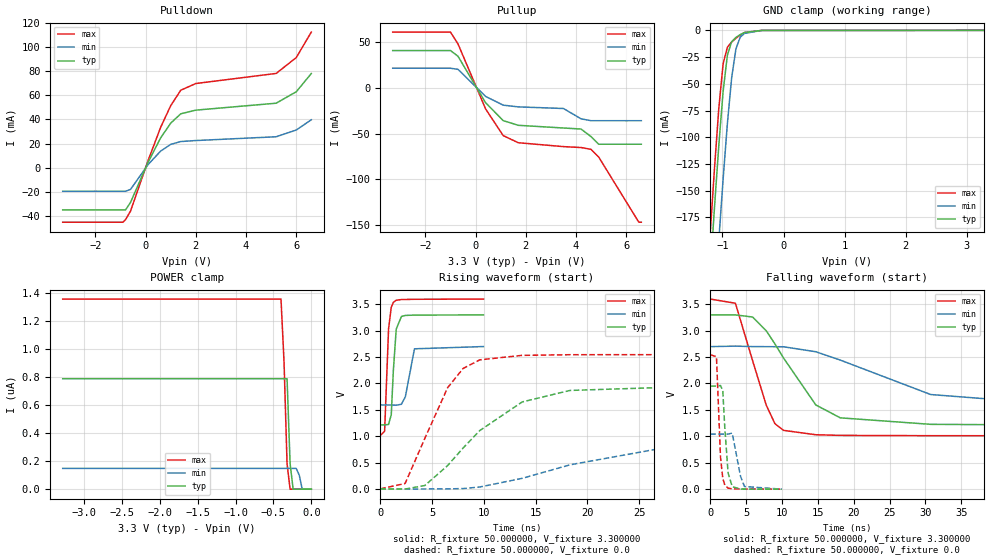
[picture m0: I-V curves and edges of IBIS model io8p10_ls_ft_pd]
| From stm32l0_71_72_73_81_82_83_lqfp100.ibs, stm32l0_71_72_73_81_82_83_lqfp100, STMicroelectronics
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|   Model io8p10_ls_ft_pd
[Model]  io8p10_ls_ft_pd
Model_type I/O
Polarity   Non-Inverting
Enable   Active-Low
Vinl =   0.990000V
Vinh =   2.310000V
Vmeas =  1.650000V
Cref =   50.000000pF
Rref =   100.000000M
Vref =   0.0V
C_comp   4.606100pF   4.563500pF   4.706200pF
[Temperature Range]   25.000000   0.125000k   -40.000000
[Pullup Reference]   3.300000V   2.700000V   3.600000V
[Pulldown Reference]   0.0V   0.0V   0.0V
[POWER Clamp Reference]   3.300000V   2.700000V   3.600000V
[GND Clamp Reference]   0.0V   0.0V   0.0V
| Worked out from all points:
|   slope of the pulldown table from 0 to 0.495 V, typ, clamps not added: 23.6 ohm
|   slope of the pullup table from 0 to 0.495 V, typ, clamps not added: 24.9 ohm
|   GND clamp passes 1 mA (typ) near -0.59 V on its own axis
|   rising waveform, R_fixture 50.000000, V_fixture 3.300000: 20-80 % time 317ps typ, 426ps min, 300ps max; typ from 1.21 V to 3.3 V
|   rising waveform, R_fixture 50.000000, V_fixture 0.0: 20-80 % time 6.51ns typ, 13.6ns min, 3.48ns max; typ from 0 V to 1.95 V
|   falling waveform, R_fixture 50.000000, V_fixture 3.300000: 20-80 % time 6.08ns typ, 12.6ns min, 3.34ns max; typ from 3.3 V to 1.21 V
|   falling waveform, R_fixture 50.000000, V_fixture 0.0: 20-80 % time 520ps typ, 682ps min, 458ps max; typ from 1.95 V to 0 V
[Pulldown]
|Voltage   I(typ)   I(min)   I(max)
-3.3V     -34.78mA   -19.34mA   -44.89mA
-900mV    -34.78mA   -19.34mA   -44.89mA
-800mV    -34.78mA   -19.34mA   -42.84mA
-600mV    -28.56mA   -17.8mA    -35.74mA
100mV     4.638mA    2.744mA    6.076mA
600mV     24.8mA     13.84mA    33.52mA
1V        36.92mA    19.39mA    51.35mA
1.4V      44.67mA    21.76mA    64.17mA
2V        47.7mA     22.58mA    69.7mA
5.2V      53.44mA    25.71mA    78.04mA
6V        62.89mA    31.28mA    91.14mA
6.6V      77.95mA    39.75mA    112.2mA
[Pullup]
|Voltage   I(typ)   I(min)   I(max)
-3.3V     40.48mA    21.18mA    60.57mA
-1V       40.48mA    21.18mA    60.57mA
-700mV    34.22mA    19.98mA    47.65mA
400mV     -16.48mA   -9.566mA   -23.24mA
1.1V      -35.89mA   -19.06mA   -52.22mA
1.7V      -41.02mA   -20.95mA   -60.01mA
3.5V      -43.95mA   -22.7mA    -64.24mA
4.2V      -45.08mA   -33.97mA   -65.24mA
4.6V      -53.38mA   -36mA      -67.23mA
4.9V      -61.64mA   -36mA      -75.5mA
6.5V      -61.64mA   -36mA      -146.6mA
6.6V      -61.64mA   -36mA      -146.6mA
[GND_clamp]
|Voltage   I(typ)   I(min)   I(max)
-3.3V     -2.275A    -2.356A    -2.249A
-1.2V     -226mA     -318.7mA   -189.2mA
-1.13V    -164.9mA   -256.6mA   -128.3mA
-1.06V    -107.5mA   -196.5mA   -72.79mA
-990mV    -57.33mA   -139.4mA   -31.4mA
-920mV    -23.23mA   -87.33mA   -15.73mA
-850mV    -10.59mA   -44.46mA   -10.94mA
-780mV    -6.551mA   -17.26mA   -7.364mA
-710mV    -3.945mA   -6.365mA   -4.316mA
-640mV    -1.966mA   -2.806mA   -1.983mA
-360mV    -10.16uA   -28.12uA   -6.105uA
3.28V     73.92uA    88.6uA     51.45uA
[POWER_clamp]
|Voltage   I(typ)   I(min)   I(max)
-3.28V    786.7nA    148nA      1.355uA
-400mV    786.7nA    148nA      1.355uA
-360mV    786.7nA    148nA      908.2nA
-320mV    786.7nA    148nA      180.5nA
-280mV    182.6nA    148nA      0A
-240mV    0A         148nA      0A
-200mV    0A         148nA      0A
-160mV    0A         101.6nA    0A
-120mV    0A         0A         0A
0V        0A         0A         0A
[Ramp]
| variable   typ   min   max
dV/dt_r  1.17009/6.49858n   0.61787/13.51358n   1.52712/3.47686n
dV/dt_f  1.25100/6.07192n   0.64098/12.43359n   1.55262/3.33325n
R_load = 50.000000
[Rising Waveform]
R_fixture= 50.000000
V_fixture= 3.300000
V_fixture_min= 2.700000
V_fixture_max= 3.600000
|time   V(typ)   V(min)   V(max)
0s        1.213V     1.591V     1.011V
420.4ps   1.212V     1.591V     1.095V
800.8ps   1.222V     1.591V     3.033V
1.061ns   1.405V     1.591V     3.443V
1.261ns   2.236V     1.589V     3.535V
1.542ns   3.029V     1.586V     3.575V
2.042ns   3.267V     1.604V     3.589V
2.422ns   3.288V     1.746V     3.59V
3.303ns   3.294V     2.655V     3.594V
9.97ns    3.298V     2.698V     3.598V
[Rising Waveform]
R_fixture= 50.000000
V_fixture= 0.0
V_fixture_min= 0.0
V_fixture_max= 0.0
|time   V(typ)   V(min)   V(max)
0s        172.6uV    66.71uV    965uV
2.402ns   -2.737mV   -5.252mV   102.4mV
4.304ns   63.98mV    -1.082mV   956.7mV
6.507ns   441.7mV    -335.5uV   1.918V
8.008ns   776.3mV    6.19mV     2.283V
9.61ns    1.105V     35.45mV    2.446V
13.71ns   1.648V     200.1mV    2.531V
18.32ns   1.866V     455.7mV    2.543V
31.43ns   1.948V     920.7mV    2.545V
49.85ns   1.95V      1.042V     2.545V
[Falling Waveform]
R_fixture= 50.000000
V_fixture= 3.300000
V_fixture_min= 2.700000
V_fixture_max= 3.600000
|time   V(typ)   V(min)   V(max)
0s        3.298V     2.698V     3.598V
3.504ns   3.298V     2.707V     3.519V
5.906ns   3.258V     2.699V     2.429V
7.808ns   2.996V     2.697V     1.588V
9.009ns   2.75V      2.696V     1.24V
10.21ns   2.483V     2.695V     1.113V
14.71ns   1.594V     2.601V     1.03V
18.12ns   1.35V      2.443V     1.018V
30.73ns   1.227V     1.791V     1.012V
49.85ns   1.213V     1.591V     1.011V
[Falling Waveform]
R_fixture= 50.000000
V_fixture= 0.0
V_fixture_min= 0.0
V_fixture_max= 0.0
|time   V(typ)   V(min)   V(max)
0s        1.95V      1.042V     2.545V
860.9ps   1.95V      1.042V     2.506V
1.421ns   1.962V     1.042V     613.8mV
1.742ns   1.867V     1.042V     204.1mV
2.022ns   1.172V     1.042V     79.75mV
2.482ns   307.5mV    1.042V     19.76mV
3.063ns   47.54mV    1.062V     6.106mV
4.204ns   2.45mV     248.9mV    3.951mV
4.765ns   1.646mV    50.63mV    2.881mV
9.97ns    172.6uV    66.71uV    965uV
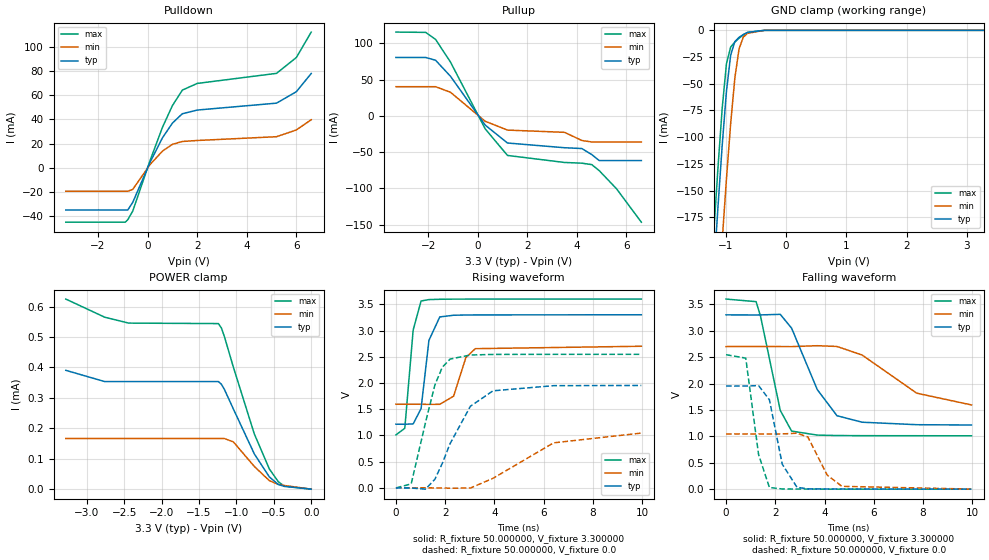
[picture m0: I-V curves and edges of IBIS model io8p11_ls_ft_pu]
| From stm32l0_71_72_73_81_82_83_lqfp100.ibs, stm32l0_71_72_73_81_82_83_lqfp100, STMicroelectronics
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|   Model io8p11_ls_ft_pu
[Model]  io8p11_ls_ft_pu
Model_type I/O
Polarity   Non-Inverting
Enable   Active-Low
Vinl =   0.990000V
Vinh =   2.310000V
Vmeas =  1.650000V
Cref =   50.000000pF
Rref =   100.000000M
Vref =   0.0V
C_comp   4.606100pF   4.563500pF   4.706200pF
[Temperature Range]   25.000000   0.125000k   -40.000000
[Pullup Reference]   3.300000V   2.700000V   3.600000V
[Pulldown Reference]   0.0V   0.0V   0.0V
[POWER Clamp Reference]   3.300000V   2.700000V   3.600000V
[GND Clamp Reference]   0.0V   0.0V   0.0V
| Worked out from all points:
|   slope of the pulldown table from 0 to 0.495 V, typ, clamps not added: 23.6 ohm
|   slope of the pullup table from 0 to 0.495 V, typ, clamps not added: 24.9 ohm
|   GND clamp passes 1 mA (typ) near -0.59 V on its own axis
|   rising waveform, R_fixture 50.000000, V_fixture 3.300000: 20-80 % time 319ps typ, 429ps min, 281ps max; typ from 1.22 V to 3.3 V
|   rising waveform, R_fixture 50.000000, V_fixture 0.0: 20-80 % time 1.22ns typ, 2.23ns min, 756ps max; typ from 0.002 V to 1.95 V
|   falling waveform, R_fixture 50.000000, V_fixture 3.300000: 20-80 % time 1.19ns typ, 2.02ns min, 694ps max; typ from 3.3 V to 1.22 V
|   falling waveform, R_fixture 50.000000, V_fixture 0.0: 20-80 % time 531ps typ, 696ps min, 441ps max; typ from 1.95 V to 0.002 V
[Pulldown]
|Voltage   I(typ)   I(min)   I(max)
-3.3V     -34.78mA   -19.34mA   -44.89mA
-900mV    -34.78mA   -19.34mA   -44.89mA
-800mV    -34.78mA   -19.34mA   -42.84mA
-600mV    -28.56mA   -17.8mA    -35.75mA
100mV     4.638mA    2.744mA    6.076mA
600mV     24.8mA     13.84mA    33.52mA
1V        36.93mA    19.4mA     51.35mA
1.4V      44.67mA    21.76mA    64.17mA
2V        47.71mA    22.58mA    69.7mA
5.2V      53.42mA    25.71mA    78.01mA
6V        62.87mA    31.27mA    91.1mA
6.6V      77.92mA    39.75mA    112.1mA
[Pullup]
|Voltage   I(typ)   I(min)   I(max)
-3.3V     80.52mA    40.21mA    115.5mA
-2.1V     80.52mA    40.21mA    115.1mA
-1.7V     76.64mA    40.21mA    105.4mA
-1.1V     54.61mA    32.55mA    74.2mA
300mV     -12.7mA    -7.449mA   -17.83mA
1.2V      -37.42mA   -19.62mA   -54.57mA
3.5V      -43.94mA   -22.7mA    -64.24mA
4.2V      -45.07mA   -33.96mA   -65.24mA
4.6V      -53.38mA   -35.99mA   -67.22mA
4.9V      -61.63mA   -35.99mA   -75.49mA
5.6V      -61.63mA   -35.99mA   -100.6mA
6.6V      -61.63mA   -35.99mA   -146.6mA
[GND_clamp]
|Voltage   I(typ)   I(min)   I(max)
-3.3V     -2.275A    -2.356A    -2.249A
-1.2V     -226mA     -318.7mA   -189.2mA
-1.13V    -164.9mA   -256.6mA   -128.3mA
-1.06V    -107.5mA   -196.5mA   -72.78mA
-990mV    -57.32mA   -139.4mA   -31.39mA
-920mV    -23.22mA   -87.32mA   -15.73mA
-850mV    -10.58mA   -44.45mA   -10.94mA
-780mV    -6.539mA   -17.25mA   -7.356mA
-710mV    -3.933mA   -6.349mA   -4.308mA
-640mV    -1.955mA   -2.79mA    -1.975mA
-360mV    -2.06uA    -16.21uA   -459.5nA
3.28V     0A         0A         0A
[POWER_clamp]
|Voltage   I(typ)   I(min)   I(max)
-3.28V    390.5uA    166.4uA    624.7uA
-2.76V    353.6uA    166.4uA    565.1uA
-2.44V    353.6uA    166.4uA    545.7uA
-1.24V    353.6uA    166.4uA    544.1uA
-1.2V     344.6uA    166.4uA    529.4uA
-1.16V    327.5uA    166.4uA    501.1uA
-1.04V    263.2uA    155.2uA    400.5uA
-760mV    115.6uA    74.53uA    180.9uA
-560mV    40.33uA    28.04uA    66.46uA
-440mV    15.38uA    15.6uA     24.56uA
-360mV    9.136uA    12.12uA    10.1uA
0V        0A         0A         0A
[Ramp]
| variable   typ   min   max
dV/dt_r  1.17069/1.21841n   0.60824/2.15427n   1.52731/0.75448n
dV/dt_f  1.24866/1.18982n   0.57654/1.82455n   1.55238/0.69218n
R_load = 50.000000
[Rising Waveform]
R_fixture= 50.000000
V_fixture= 3.300000
V_fixture_min= 2.700000
V_fixture_max= 3.600000
|time   V(typ)   V(min)   V(max)
0s        1.215V     1.595V     1.011V
360.4ps   1.214V     1.595V     1.137V
700.7ps   1.221V     1.595V     3.009V
1.021ns   1.511V     1.595V     3.562V
1.341ns   2.812V     1.592V     3.589V
1.782ns   3.259V     1.594V     3.595V
2.342ns   3.291V     1.749V     3.598V
2.843ns   3.295V     2.486V     3.598V
3.223ns   3.297V     2.654V     3.599V
9.97ns    3.3V       2.7V       3.599V
[Rising Waveform]
R_fixture= 50.000000
V_fixture= 0.0
V_fixture_min= 0.0
V_fixture_max= 0.0
|time   V(typ)   V(min)   V(max)
0s        1.512mV    1.899mV    585.8uV
620.6ps   -1.135mV   1.964mV    77.77mV
1.201ns   -22.76mV   2.148mV    1.245V
1.582ns   164.9mV    1.636mV    1.961V
1.882ns   467.4mV    -356.7uV   2.299V
2.202ns   846.4mV    -4.144mV   2.456V
3.023ns   1.556V     -1.315mV   2.533V
3.944ns   1.851V     184.2mV    2.544V
6.406ns   1.949V     859.9mV    2.546V
9.97ns    1.953V     1.046V     2.546V
[Falling Waveform]
R_fixture= 50.000000
V_fixture= 3.300000
V_fixture_min= 2.700000
V_fixture_max= 3.600000
|time   V(typ)   V(min)   V(max)
0s        3.3V       2.7V       3.599V
1.221ns   3.298V     2.7V       3.55V
1.401ns   3.299V     2.7V       3.274V
2.202ns   3.31V      2.7V       1.492V
2.663ns   3.048V     2.699V     1.1V
3.704ns   1.887V     2.716V     1.024V
4.505ns   1.391V     2.702V     1.016V
5.526ns   1.268V     2.54V      1.013V
7.748ns   1.221V     1.817V     1.012V
9.97ns    1.215V     1.595V     1.011V
[Falling Waveform]
R_fixture= 50.000000
V_fixture= 0.0
V_fixture_min= 0.0
V_fixture_max= 0.0
|time   V(typ)   V(min)   V(max)
0s        1.953V     1.046V     2.546V
800.8ps   1.953V     1.046V     2.481V
1.321ns   1.961V     1.046V     656.5mV
1.762ns   1.692V     1.046V     31.84mV
2.282ns   474.1mV    1.046V     4.401mV
2.883ns   35.53mV    1.06V      2.955mV
3.323ns   6.812mV    988.7mV    2.219mV
4.104ns   3.919mV    270.4mV    1.405mV
4.705ns   3.159mV    54.34mV    1.071mV
9.97ns    1.512mV    1.899mV    585.8uV
